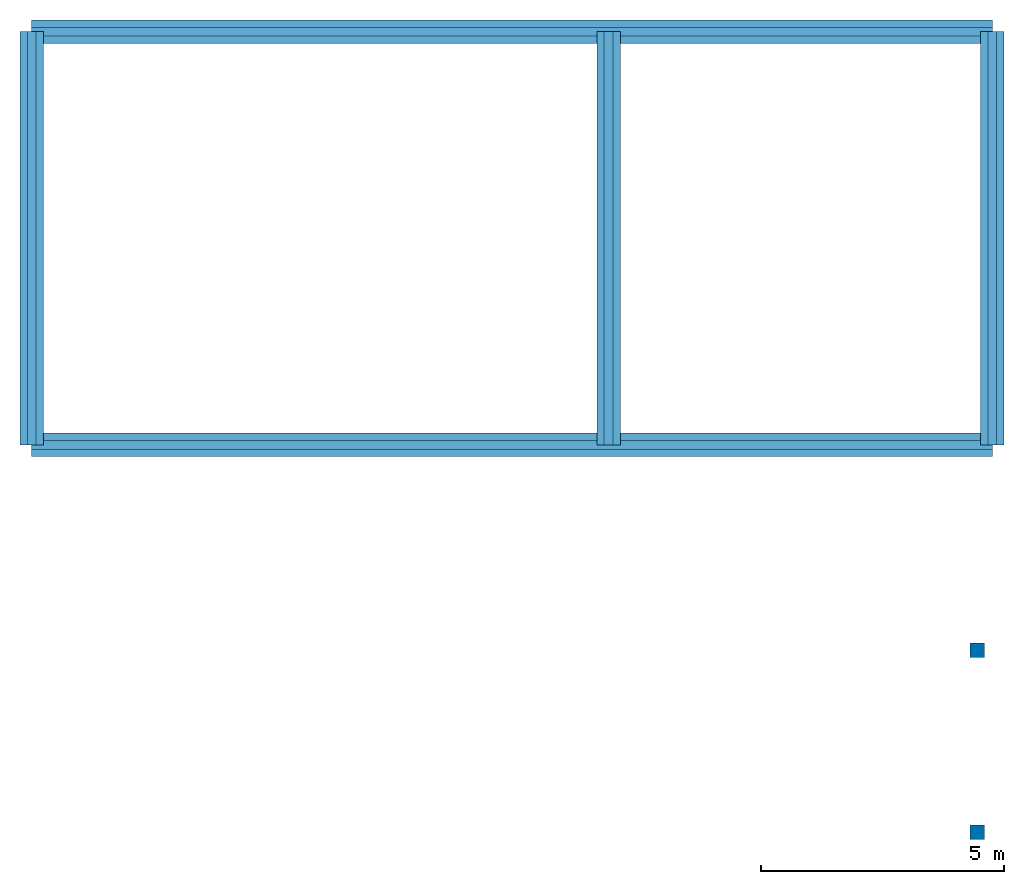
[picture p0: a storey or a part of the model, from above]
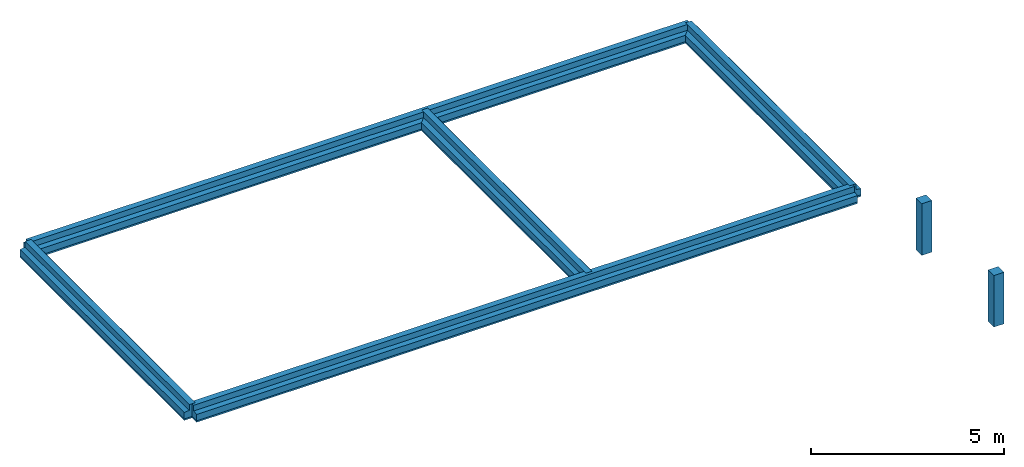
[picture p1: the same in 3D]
Properties of the parts of a building model (IFC2X3)

# File
Description: ViewDefinition [CoordinationView_V2.0], Option [Drawing Scale: 100.000000], Option [Elements to export: Visible elements (on all stories)], Option [Partial Structure Display: Entire Model], Option [IFC Domain: All], Option [Structural Function: All Elements], Option [Convert Grid elements: On], Option [Convert IFC Annotations and ARCHICAD 2D elements: Off], Option [Convert 2D symbols of Doors and Windows: Off], Option [Export geometries that Participates in Collision Detection only: Off], Option [Split complex elements: Off], Option [Material Preservation: Explode where necessary], Option [Elements in Solid Element Operations: Extruded/revolved], Option [Elements with junctions: Extruded/revolved without junctions], Option [Slabs with slanted edge(s): Extruded], Option [IFC Site Location: At Project Origin], Option [Curtain Wall export mode: Container Element], Option [Railing export mode: Single Element], Option [Stair export mode: Container Element], Option [Properties To Export: All properties], Option [Space containment: Off], Option [Bounding Box: Off], Option [Geometry to type objects: Off], Option [Element Properties: Off], Option [Building Material Properties: Off], Option [Element Parameters: Off], Option [Component Parameters: Off], Option [IFC Base Quantities: Off], Option [Door Window Parameters: Off], Option [IFC Space boundaries: Off], Option [ARCHICAD Zone Categories as IFC Space classification data: Off], Option [Element Classifications: On]
File name: E:\(1)_Serveur_prof_commun\__1 TB\24-Projet Aménagement de Garage\(1) Prépa Projet\ESQ_ETL_Projet Aménagement garage.ifc
Time: 2020-08-21T18:02:37
Author: Architect
Organization: Building Designer Office
Written by: The EXPRESS Data Manager Version 5.02.0100.09 : 26 Sep 2013
Made in: IFC file generated by GRAPHISOFT ARCHICAD 24.0.0 FRA FULL Windows version (IFC add-on version: 3008 FRA FULL).
Authorization: The authorising person

# IfcSite, Site
RefLatitude: 48, 52, 0, 0; RefLongitude: 2, 20, 0, 0; RefElevation: 26 m

# IfcBuildingStorey (3)
In: Bâtiment
Name | Elevation (m)
Sous-sol | -2.8
Rez-de-chaussée | 0
1er étage | 2.8

# IfcBeam: Bois massif 100 x 220 (16)
Type - PredefinedType: BEAM
Classification: Poutre (Classification ARCHICAD); Material: Bois massif
Pset_BeamCommon - LoadBearing: yes; IsExternal: no; Reference: Bois massif 100 x 220
Name | In | Span (m) | Slope (deg) | Renovation Status
POUTRE-003 | Rez-de-chaussée | 8.18772 | 9.09 | Existing
8 x POUTRE-006 | Rez-de-chaussée | 4.43017 | 0 | To Be Demolished
POUTRE-006 | Rez-de-chaussée | 4.43017 | 0 | Existing
6 x POUTRE-004 | 1er étage | 7.83123 | 0 | Existing

# IfcBeam: Bois massif 150 x 150 (2)
In: Rez-de-chaussée
Type - PredefinedType: BEAM
Classification: Poutre (Classification ARCHICAD); Material: Bois massif
Pset_BeamCommon - Span: 7.78863 m; Slope: 0 deg; LoadBearing: yes; IsExternal: no; Reference: Bois massif 150 x 150
AC_Pset_RenovationAndPhasing - Renovation Status: To Be Demolished

# IfcBeam: Tete de poteau (2) 750 x 720, POUTRE-002
In: 1er étage
Type - PredefinedType: BEAM
Classification: Poutre (Classification ARCHICAD); Material: Béton
Pset_BeamCommon - Span: 0.27 m; Slope: 0 deg; LoadBearing: yes; IsExternal: no; Reference: Tete de poteau (2) 750 x 720
AC_Pset_RenovationAndPhasing - Renovation Status: Existing

# IfcBeam: Tete de poteau 750 x 600 (2)
In: 1er étage
Type - PredefinedType: BEAM
Classification: Poutre (Classification ARCHICAD); Material: Béton
Pset_BeamCommon - Span: 0.27 m; Slope: 0 deg; LoadBearing: yes; IsExternal: no; Reference: Tete de poteau 750 x 600
AC_Pset_RenovationAndPhasing - Renovation Status: Existing

# IfcBuildingElementPart (33)
Name | In | Material
5 x Béton maigre | Sous-sol | Béton maigre
5 x Béton | Sous-sol | Béton
7 x Brique ciment (extérieur) | Rez-de-chaussée | Brique ciment (extérieur)
7 x Finition ext - Crépis | Rez-de-chaussée | Finition ext - Crépis
3 x Finition int - Plaque de plâtre | Rez-de-chaussée | Finition int - Plaque de plâtre
3 x Isolation - Laine de verre | Rez-de-chaussée | Isolation - Laine de verre
Etanchéité | Rez-de-chaussée | Etanchéité
Bois - Liteaux | Rez-de-chaussée | Bois - Liteaux
Tuile terre-cuite | Rez-de-chaussée | Tuile terre-cuite

# IfcBuildingElementProxy: Gouttière 24, MOBILIER-003
In: 1er étage
Type - ElementType: CONSTRUCTION ELEMENT; PredefinedType: USERDEFINED
Classification: Elément de construction (Classification ARCHICAD)
AC_Pset_RenovationAndPhasing - Renovation Status: Existing

# IfcBuildingElementProxy: Tuyau descente complexe 24, MOBILIER-004
In: Rez-de-chaussée
Type - ElementType: CONSTRUCTION ELEMENT; PredefinedType: USERDEFINED
Classification: Elément de construction (Classification ARCHICAD)
AC_Pset_RenovationAndPhasing - Renovation Status: Existing

# IfcColumn: Béton armé (Coulé) 270 x 270 (4)
In: Rez-de-chaussée
Type - PredefinedType: COLUMN
Classification: Poteau (Classification ARCHICAD); Material: Béton armé (Coulé)
Pset_ColumnCommon - Slope: 90 deg; LoadBearing: yes; IsExternal: yes; Reference: Béton armé (Coulé) 270 x 270
AC_Pset_RenovationAndPhasing - Renovation Status: Existing

# IfcColumn: Béton armé (Coulé) 300 x 300 (2)
In: Sous-sol
Type - PredefinedType: COLUMN
Classification: Poteau (Classification ARCHICAD); Material: Béton armé (Coulé)
Pset_ColumnCommon - Slope: 90 deg; LoadBearing: yes; IsExternal: yes; Reference: Béton armé (Coulé) 300 x 300
AC_Pset_RenovationAndPhasing - Renovation Status: Existing

# IfcDoor: Porte 24, PORTE-004
In: Rez-de-chaussée
Type - OperationType: SINGLE_SWING_LEFT; ParameterTakesPrecedence: no; Sizeable: no
OverallHeight: 2.12 m; OverallWidth: 0.93 m; Classification: Porte (Classification ARCHICAD)
Pset_DoorCommon - ThermalTransmittance: 0; GlazingAreaFraction: 0.681468; IsExternal: no
AC_Pset_RenovationAndPhasing - Renovation Status: Existing

# IfcDoor: Porte 24, PORTE-003
In: Rez-de-chaussée
Type - OperationType: SINGLE_SWING_RIGHT; ParameterTakesPrecedence: no; Sizeable: no
OverallHeight: 2.3 m; OverallWidth: 0.9 m; Classification: Porte (Classification ARCHICAD)
Pset_DoorCommon - ThermalTransmittance: 0; GlazingAreaFraction: 0.876888; IsExternal: no
AC_Pset_RenovationAndPhasing - Renovation Status: Existing

# IfcDoor: Porte double 24, PORTE-003
In: Rez-de-chaussée
Type - OperationType: DOUBLE_DOOR_SINGLE_SWING; ParameterTakesPrecedence: no; Sizeable: no
OverallHeight: 2.1 m; OverallWidth: 1.27 m; Classification: Porte (Classification ARCHICAD)
Pset_DoorCommon - ThermalTransmittance: 0; GlazingAreaFraction: 1.32978; IsExternal: no
AC_Pset_RenovationAndPhasing - Renovation Status: Existing

# IfcDoor: Porte double garage 24, PORTE-002
In: Rez-de-chaussée
Type - OperationType: DOUBLE_DOOR_SINGLE_SWING; ParameterTakesPrecedence: no; Sizeable: no
OverallHeight: 2.47 m; OverallWidth: 3.04 m; Classification: Porte (Classification ARCHICAD)
Pset_DoorCommon - ThermalTransmittance: 0; IsExternal: no
AC_Pset_RenovationAndPhasing - Renovation Status: To Be Demolished

# IfcOpeningElement: EMPTY_OPENING (2)
In: Rez-de-chaussée
Classification: Percement / Ouverture vide (Classification ARCHICAD)
AC_Pset_RenovationAndPhasing - Renovation Status: Existing
Name
PERCEMENT-002
PERCEMENT-001

# IfcRoof (6)
In: Rez-de-chaussée
Classification: Toiture (Classification ARCHICAD)
AC_Pset_RenovationAndPhasing - Renovation Status: Existing
Pset_RoofCommon - IsExternal: yes
Name | Material
TOIT-006
TOIT-001 | Volume - Etude
TOIT-002 | Volume - Etude
TOIT-004 | Volume - Etude
TOIT-005 | Tuile terre-cuite
TOIT-003 | Volume - Etude

# IfcSlab: Bois - Liteaux 183, DALLE-003
In: Rez-de-chaussée
Type - PredefinedType: FLOOR
Classification: Dalle de sol (Classification ARCHICAD); Material: Bois - Liteaux 0.183234 m
AC_Pset_RenovationAndPhasing - Renovation Status: Existing
Pset_SlabCommon - LoadBearing: yes; IsExternal: no

# IfcSlab: Bois OSB 54, DALLE-005
In: Rez-de-chaussée
Type - PredefinedType: FLOOR
Classification: Dalle de sol (Classification ARCHICAD); Material: Bois OSB 0.054 m
AC_Pset_RenovationAndPhasing - Renovation Status: To Be Demolished
Pset_SlabCommon - LoadBearing: yes; IsExternal: no

# IfcSlab: Béton armé (Coulé) 340 (3)
In: Rez-de-chaussée
Type - PredefinedType: FLOOR
Classification: Dalle de sol (Classification ARCHICAD); Material: Béton armé (Coulé) 0.34 m
AC_Pset_RenovationAndPhasing - Renovation Status: Existing
Pset_SlabCommon - LoadBearing: yes; IsExternal: no
Name
2 x DALLE-002
DALLE-004

# IfcSlab: Dallage pierre 54, DALLE-004
In: Rez-de-chaussée
Type - PredefinedType: FLOOR
Classification: Dalle de sol (Classification ARCHICAD); Material: Dallage pierre 0.054 m
AC_Pset_RenovationAndPhasing - Renovation Status: Existing
Pset_SlabCommon - LoadBearing: yes; IsExternal: no

# IfcWall: 0.0 - Mur ext: revét ext + maçonnerie 215 (4)
In: Rez-de-chaussée
Type - PredefinedType: ELEMENTEDWALL
Classification: Mur composite (Classification ARCHICAD)
Pset_ConcreteElementGeneral - ConstructionType: Murs porteurs extérieurs
AC_Pset_RenovationAndPhasing - Renovation Status: Existing
Pset_WallCommon - LoadBearing: yes; IsExternal: yes
Name
MUR_EXT-002
MUR_EXT-003
MUR_EXT-004
MUR_EXT-001

# IfcWall: 0.1 - Mur ext: revét ext + maçonnerie + doublage 10cm 315 (3)
In: Rez-de-chaussée
Type - PredefinedType: ELEMENTEDWALL
Classification: Mur composite (Classification ARCHICAD)
Pset_ConcreteElementGeneral - ConstructionType: Murs porteurs extérieurs
AC_Pset_RenovationAndPhasing - Renovation Status: Existing
Pset_WallCommon - LoadBearing: yes; IsExternal: yes

# IfcWall: Béton 100 (4)
In: Rez-de-chaussée
Type - PredefinedType: ELEMENTEDWALL
Classification: Mur composite (Classification ARCHICAD); Material: Béton
Pset_ConcreteElementGeneral - ConstructionType: Murs porteurs extérieurs
AC_Pset_RenovationAndPhasing - Renovation Status: Existing
Pset_WallCommon - LoadBearing: yes; IsExternal: yes
Name
MUR_EXT-010
MUR_EXT-007
MUR_EXT-008
MUR_EXT-009

# IfcWall: Fondation - Semelle filante 480 x 450 (5)
In: Sous-sol
Type - PredefinedType: ELEMENTEDWALL
Classification: Mur composite (Classification ARCHICAD)
Pset_ConcreteElementGeneral - ConstructionType: Murs porteurs extérieurs
AC_Pset_RenovationAndPhasing - Renovation Status: Existing
Pset_WallCommon - LoadBearing: yes; IsExternal: yes
Name
MUR_EXT-009
MUR_EXT-010
MUR_EXT-011
2 x MUR_EXT-012

# IfcWall: Volume - Etude 315 (17)
In: Rez-de-chaussée
Type - PredefinedType: ELEMENTEDWALL
Classification: Mur composite (Classification ARCHICAD); Material: Volume - Etude
Pset_ConcreteElementGeneral - ConstructionType: Murs porteurs extérieurs
AC_Pset_RenovationAndPhasing - Renovation Status: Existing
Pset_WallCommon - LoadBearing: yes; IsExternal: yes
Name
MUR_EXT-024
MUR_EXT-026
MUR_EXT-025
MUR_EXT-027
MUR_EXT-011
MUR_EXT-012
MUR_EXT-013
MUR_EXT-014
MUR_EXT-015
MUR_EXT-016
MUR_EXT-017
MUR_EXT-018
MUR_EXT-019
MUR_EXT-020
MUR_EXT-021
MUR_EXT-022
MUR_EXT-023

# IfcWallStandardCase: 2.0 - Refend: béton + enduit plâtre 2 faces 210 (9)
In: Rez-de-chaussée
Type - PredefinedType: ELEMENTEDWALL
Classification: Mur composite (Classification ARCHICAD); Material: Finition int - Enduit plâtre 0.015 m, Béton armé (Banché) 0.18 m, Finition int - Enduit plâtre 0.015 m
Pset_ConcreteElementGeneral - ConstructionType: Murs porteurs extérieurs
AC_Pset_RenovationAndPhasing - Renovation Status: Existing
Pset_WallCommon - LoadBearing: yes; IsExternal: yes
Name
2 x MUR_EXT-032
2 x MUR_EXT-029
MUR_EXT-030
MUR_EXT-031
MUR_EXT-033
MUR_EXT-034
MUR_EXT-035

# IfcWallStandardCase: Volume - Etude 315, MUR_EXT-028
In: Rez-de-chaussée
Type - PredefinedType: ELEMENTEDWALL
Classification: Mur composite (Classification ARCHICAD); Material: Volume - Etude 0.315 m
Pset_ConcreteElementGeneral - ConstructionType: Murs porteurs extérieurs
AC_Pset_RenovationAndPhasing - Renovation Status: Existing
Pset_WallCommon - LoadBearing: yes; IsExternal: yes

# IfcWindow: Fenêtre horizontale à châssis multiples 24 (4)
In: Rez-de-chaussée
Type - OperationType: DOUBLE_PANEL_VERTICAL; ParameterTakesPrecedence: no; Sizeable: no
OverallHeight: 1.5 m; Classification: Fenêtre (Classification ARCHICAD)
Pset_WindowCommon - ThermalTransmittance: 0; IsExternal: yes
AC_Pset_RenovationAndPhasing - Renovation Status: Existing
Name | OverallWidth (m) | GlazingAreaFraction
2 x FENETRE-002 | 1.18 | 1.144
FENETRE-002 | 1.36 | 1.378
FENETRE-002 | 1.75 | 1.885

# IfcWindow: Fenêtre horizontale à châssis multiples 24, FENETRE-002
In: Rez-de-chaussée
Type - OperationType: USERDEFINED; ParameterTakesPrecedence: no; Sizeable: no
OverallHeight: 1.36 m; OverallWidth: 1.85 m; Classification: Fenêtre (Classification ARCHICAD)
Pset_WindowCommon - ThermalTransmittance: 0; GlazingAreaFraction: 1.984; IsExternal: yes
AC_Pset_RenovationAndPhasing - Renovation Status: To Be Demolished
